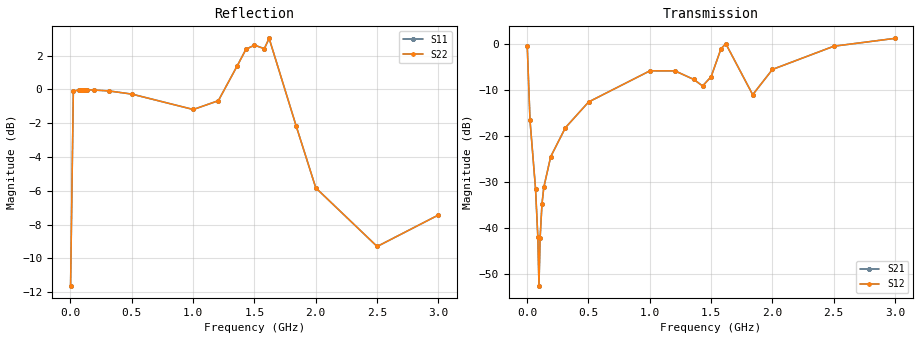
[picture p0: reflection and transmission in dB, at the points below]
!s-Parameter Generated by FASTRON Sdn. Bhd.
!FASTRON P/N : MICC-4R0X
!Keysight Technologies,E4991B,MY54100416,A.01.15
!Date: Fri Aug 28 10:06:03 2026
!Version  : Rev00 Fri Aug 28 10:06:03 2026
!Data & Calibration Information:
!PortZ  Port1:50+j0  Port2:50+j0
!When reading, reference impedance value at option line is always used.
! Remarks : This data is being provided solely for informational purposes.
!Freq	S11	S21	S12	S22
# Hz S dB R 50
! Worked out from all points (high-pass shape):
!   1601 points, 1 MHz to 3 GHz, reference 50 ohm
!   highest |S21| = 1.25 dB at 3 GHz (marker M1); lowest = -52.6 dB at 96.59 MHz (marker M2)
!   |S21| within 3 dB of the highest: 1.569 GHz to 1.668 GHz (99.32 MHz wide, 6.14 % of centre); 2.285 GHz to end of sweep (the widest 2 of 3)
!   lowest |S11| = -11.6 dB at 1 MHz (marker M3), VSWR 1.71, Z = 50.7 + j27.4 ohm
!   |S11| at or under -10 dB: start of sweep to 1.414 MHz
!   |S22| runs from -11.6 to 3.0 dB; largest |S21 - S12| = 0
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1000000  -11.62 73.4  -0.37 -15.2  -0.37 -15.2  -11.62 73.4
2.34925e7  -0.12 8.5  -16.59 -80.5  -16.59 -80.5  -0.12 8.5
6.84775e7  -0.02 1.5  -31.43 -83.5  -31.43 -83.5  -0.02 1.5
8.722125e7  -0.02 0.4  -41.90 -72.6  -41.90 -72.6  -0.02 0.4
9.659312e7  -0.02 -0.0  -52.57 5.2  -52.57 5.2  -0.02 -0.0
1.05965e8  -0.02 -0.4  -42.20 71.8  -42.20 71.8  -0.02 -0.4
1.2096e8  -0.02 -1.0  -34.87 81.6  -34.87 81.6  -0.02 -1.0
1.35955e8  -0.02 -1.6  -31.18 83.5  -31.18 83.5  -0.02 -1.6
1.921862e8  -0.04 -3.4  -24.51 84.2  -24.51 84.2  -0.04 -3.4
3.121462e8  -0.09 -7.1  -18.19 81.6  -18.19 81.6  -0.09 -7.1
5.014581e8  -0.28 -13.6  -12.59 75.4  -12.59 75.4  -0.28 -13.6
1.001916e9  -1.19 -30.8  -5.81 60.7  -5.81 60.7  -1.19 -30.8
1.206223e9  -0.67 -30.5  -5.82 66.6  -5.82 66.6  -0.67 -30.5
1.359922e9  1.39 -19.9  -7.70 104.6  -7.70 104.6  1.39 -19.9
1.431148e9  2.37 -7.7  -9.11 149.6  -9.11 149.6  2.37 -7.7
1.5005e9  2.62 13.1  -7.11 -136.0  -7.11 -136.0  2.62 13.1
1.581098e9  2.41 42.3  -1.02 -88.4  -1.02 -88.4  2.41 42.3
1.62046e9  3.02 45.5  0.09 -89.5  0.09 -89.5  3.02 45.5
1.839762e9  -2.14 11.5  -11.01 -33.7  -11.01 -33.7  -2.14 11.5
2.000958e9  -5.83 -16.4  -5.51 15.8  -5.51 15.8  -5.83 -16.4
2.501416e9  -9.30 -71.5  -0.46 20.0  -0.46 20.0  -9.30 -71.5
3e9  -7.44 -100.4  1.25 21.2  1.25 21.2  -7.44 -100.4
